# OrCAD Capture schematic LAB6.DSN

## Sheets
1 PAGE4: size A
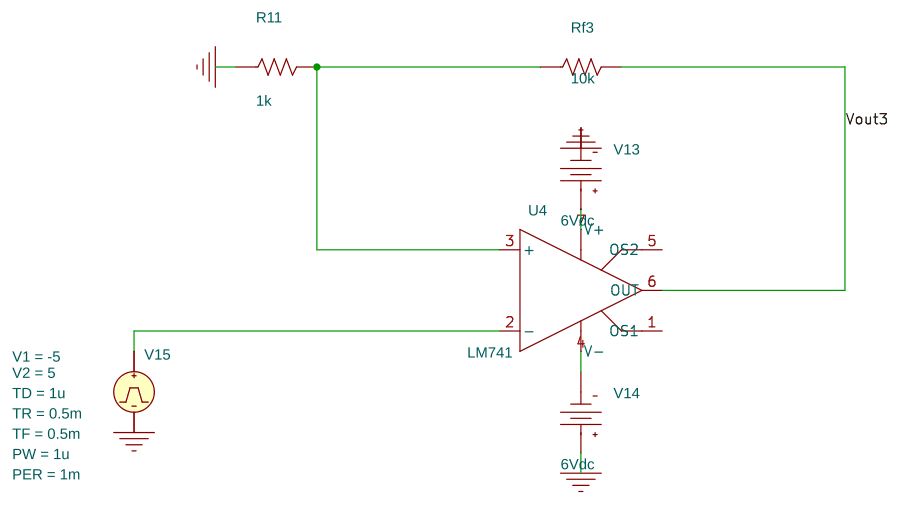
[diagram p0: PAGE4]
2 PAGE3: size A
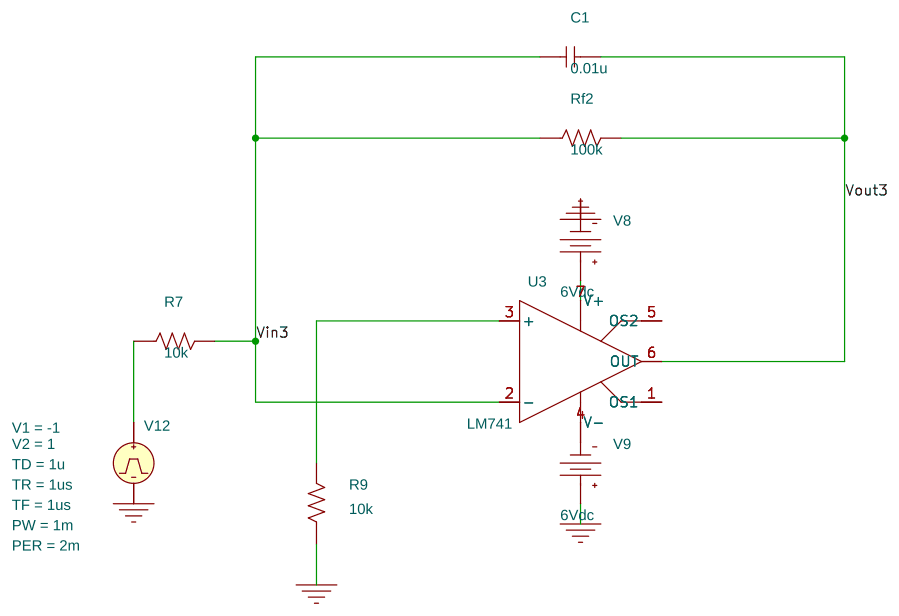
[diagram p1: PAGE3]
3 PAGE2: size A
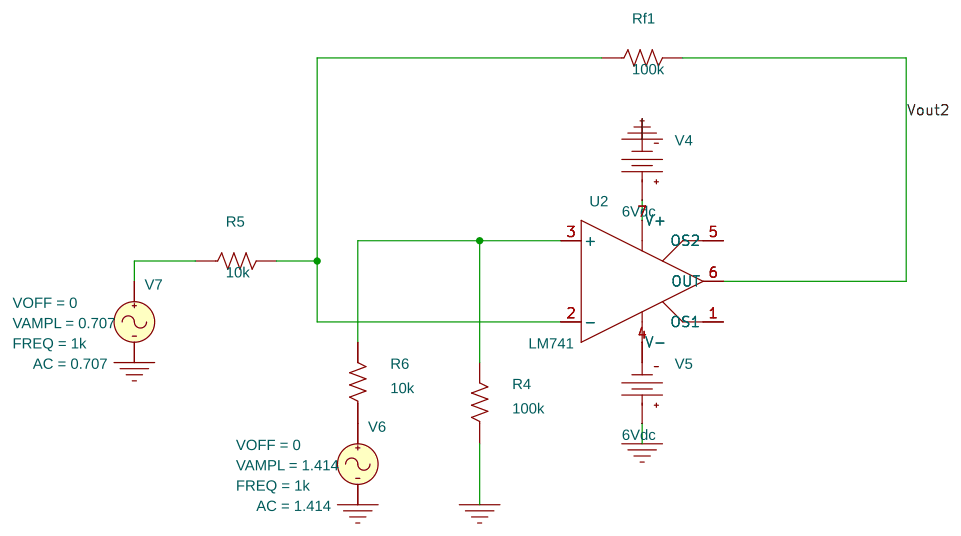
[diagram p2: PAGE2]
4 PAGE1: size A

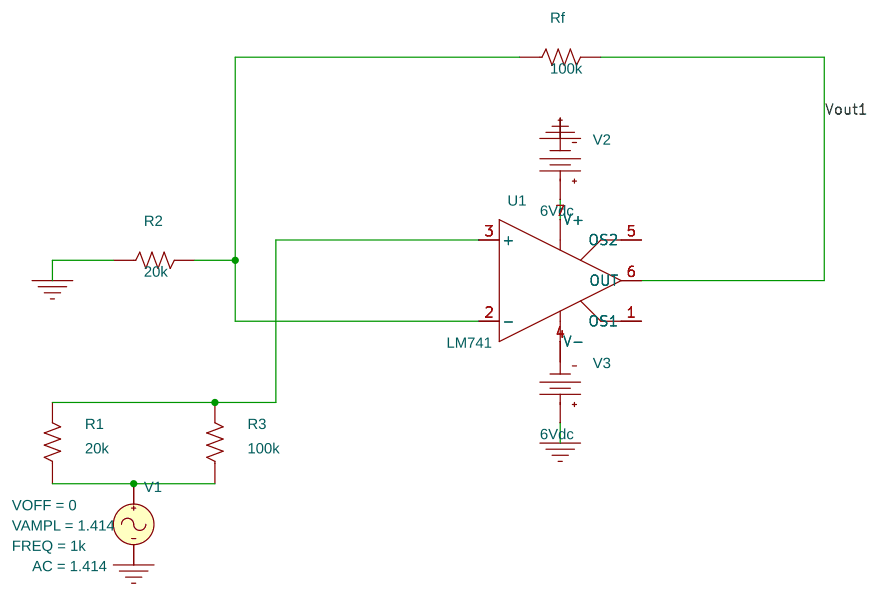
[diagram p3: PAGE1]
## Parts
sheet PAGE1
R1  20k  [AX/RC05]
R2  20k  [AX/RC05]
R3  100k  [AX/RC05]
Rf  100k  [AX/RC05]
U1  LM741  [DIP.100/8/W.300/L.450]
V1  VSIN
V2  VDC
V3  VDC
sheet PAGE2
R4  100k  [AX/RC05]
R5  10k  [AX/RC05]
R6  10k  [AX/RC05]
Rf1  100k  [AX/RC05]
U2  LM741  [DIP.100/8/W.300/L.450]
V4  VDC
V5  VDC
V6  VSIN
V7  VSIN
sheet PAGE3
C1  0.01u  [RAD/CK05]
R7  10k  [AX/RC05]
R9  10k  [AX/RC05]
Rf2  100k  [AX/RC05]
U3  LM741  [DIP.100/8/W.300/L.450]
V8  VDC
V9  VDC
V12  VPULSE
sheet PAGE4
R11  1k  [AX/RC05]
Rf3  10k  [AX/RC05]
U4  LM741  [DIP.100/8/W.300/L.450]
V13  VDC
V14  VDC
V15  VPULSE

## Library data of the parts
R1-R7 R9 R11 Rf Rf1-Rf3 = R
U1-U4 = LM741
V1 V6 = VSIN: AC: 1.414; FREQ: 1k; VAMPL: 1.414; VOFF: 0
V2-V5 V8 V9 V13 V14 = VDC: DC: 6Vdc
V7 = VSIN: AC: 0.707; FREQ: 1k; VAMPL: 0.707; VOFF: 0
C1 = C
V12 = VPULSE: PER: 2m; PW: 1m; TD: 1u; TF: 1us; TR: 1us; V1: -1; V2: 1
V15 = VPULSE: PER: 1m; PW: 1u; TD: 1u; TF: 0.5m; TR: 0.5m; V1: -5; V2: 5

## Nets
Vin3: C1.1 R7.2 Rf2.1 U3.2(-)
0: R2.1 R4.1 R9.1 R11.1 V1.2(-) V2.1(-) V3.0(+) V4.1(-) V5.0(+) V6.2(-) V7.2(-) V8.1(-) V9.0(+) V12.2(-) V13.1(-) V14.0(+) V15.2(-)
Vout1: Rf.2 U1.6(OUT)
Vout2: Rf1.2 U2.6(OUT)
Vout3: C1.2 Rf2.2 U3.6(OUT)
Vout3 (page PAGE4): Rf3.2 U4.6(OUT)
N01467: R1.2 R3.2 U1.3(+)
N01535: R2.2 Rf.1 U1.2(-)
N01587: U1.7(V+) V2.0(+)
N01822: U1.4(V-) V3.1(-)
N02072: R1.1 R3.1 V1.1(+)
N03106: R4.2 R6.2 U2.3(+)
N03148: R5.1 V7.1(+)
N03154: R5.2 Rf1.1 U2.2(-)
N03210: U2.7(V+) V4.0(+)
N03317: U2.4(V-) V5.1(-)
N03707: R6.1 V6.1(+)
N04231: U3.7(V+) V8.0(+)
N04367: R7.1 V12.1(+)
N04371: R9.2 U3.3(+)
N08323: U3.4(V-) V9.1(-)
N08874: U4.2(-) V15.1(+)
N08924: U4.7(V+) V13.0(+)
N08930: R11.2 Rf3.1 U4.3(+)
N10158: U4.4(V-) V14.1(-)

Not connected (* = marked no-connect by the designer): U1 1(OS1) 5(OS2); U2 1(OS1) 5(OS2); U3 1(OS1) 5(OS2); U4 1(OS1) 5(OS2)
